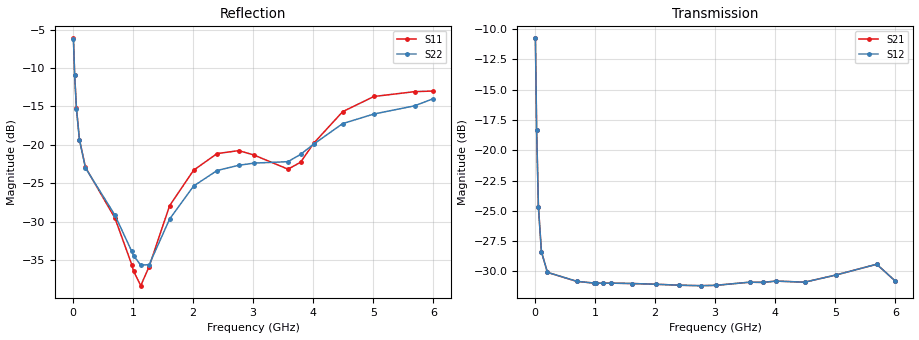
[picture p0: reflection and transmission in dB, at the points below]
! Integrated Device Technology
! Corporate Headquarters
! 6024 Silver Creek Valley Road
! San Jose, CA 95138  USA
! Phone:  1-408-284-8200
! Toll Free:  1-800-223-1366
! Webpage:  http://www.idt.com/
! Timing and RF Division
! 515 Groton Road, Suite 102
! Westford, MA 01886-6024
! Device:  F1951
! Description: 6-bit 0.5 dB Digital Step Attenuator
! Frequency:  100.0 -  4000.00 MHz
! Package:  4x4 mm Thin QFN Plastic Package: 24 pin
! Ports:  2 RF, 6 DC
!  Pin  1  = NC
!  Pin  2  = RF1  =  Port 1
!  Pin  3  = GND
!  Pin  4  = NC
!  Pin  5  = Serial Data Out (SDO)
!  Pin  6  = NC
!  Pin  7  = Reset Bar ( RSTb)
!  Pin  8  = Clock (CLK)
!  Pin  9  = Chip Select Bar (CSb)
!  Pin 10  = NC
!  Pin 11  = Serial Data In (SDI)
!  Pin 12  = NC
!  Pin 13  = NC
!  Pin 14  = VDD
!  Pin 15  = NC
!  Pin 16  = GND
!  Pin 17  = RF2  =  Port 2
!  Pin 18  = NC
!  Pin 19  = GND
!  Pin 20  = GND
!  Pin 21  = GND
!  Pin 22  = GND
!  Pin 23  = GND
!  Pin 24  = GND
! State:  60
! Atten State:  30.0 dB
! Voltage:  +3.30 Volts
! Current:  0.478 mA
! Data:  The device was measured on a F195X evaluation board which has
!  individual transmission lines to the RF pins.  Data was collected
!  de-embedded using a Automatic Fixture Removal [AFR] (Keysight Technologies).
!  The reference plane is the edge of the package pin.
! Misc:  Lot Code  1225BCA
!  Action Tracker AT0399
! Date Measured:  2018-09-13
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# GHz S dB R 50
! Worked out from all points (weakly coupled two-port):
!   600 points, 10 MHz to 6 GHz, reference 50 ohm
!   highest |S21| = -10.77 dB at 10 MHz (marker M1); lowest = -31.2 dB at 2.76 GHz (marker M2)
!   lowest |S11| = -38.3 dB at 1.13 GHz (marker M3), VSWR 1.02, Z = 48.8 + j0.211 ohm
!   |S11| at or under -10 dB: 25.95 MHz to end of sweep
!   |S22| runs from -36.1 to -6.2 dB; largest |S21 - S12| = 0.00018
!   S11 on the Smith chart (normalised r, x): 10 MHz: 1.78, -1.30; 30 MHz: 1.11, -0.62; 60 MHz: 0.98, -0.35; 980 MHz: 0.97, -0.01; 6 GHz: 0.81, +0.37
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0.01  -6.14 -34.1  -10.77 -41.3  -10.78 -41.3  -6.20 -34.0
0.03  -10.86 -63.8  -18.30 -67.6  -18.30 -67.7  -10.91 -63.7
0.06  -15.21 -83.4  -24.67 -61.9  -24.68 -61.9  -15.29 -83.4
0.11  -19.30 -101.2  -28.37 -44.2  -28.38 -44.1  -19.33 -101.2
0.21  -22.91 -119.5  -30.08 -27.1  -30.08 -27.1  -22.99 -119.5
0.7  -29.50 -136.3  -30.83 -14.6  -30.82 -14.6  -29.13 -138.5
0.98  -35.56 -152.7  -30.96 -15.0  -30.96 -15.0  -33.84 -150.4
1.01  -36.41 -157.7  -30.97 -15.0  -30.97 -15.0  -34.39 -153.2
1.13  -38.31 169.8  -30.98 -15.2  -30.98 -15.2  -35.63 -170.1
1.27  -35.82 132.3  -30.97 -15.9  -30.97 -15.8  -35.58 164.1
1.61  -27.91 115.4  -31.00 -17.9  -31.00 -17.9  -29.65 134.9
2.01  -23.29 123.1  -31.06 -21.0  -31.06 -21.0  -25.35 135.4
2.4  -21.13 133.3  -31.14 -23.7  -31.14 -23.7  -23.33 140.9
2.76  -20.74 142.1  -31.18 -26.2  -31.18 -26.1  -22.65 145.2
3.01  -21.30 145.8  -31.15 -27.7  -31.15 -27.7  -22.37 146.0
3.58  -23.15 124.7  -30.89 -31.5  -30.89 -31.5  -22.18 129.2
3.79  -22.26 109.0  -30.91 -33.0  -30.91 -33.0  -21.23 122.4
4.01  -19.77 100.6  -30.80 -34.6  -30.80 -34.6  -19.89 117.0
4.49  -15.68 98.9  -30.89 -37.2  -30.89 -37.2  -17.23 115.1
5.01  -13.70 107.6  -30.30 -38.0  -30.30 -38.0  -15.98 117.3
5.69  -13.07 112.5  -29.41 -49.4  -29.41 -49.4  -14.91 110.0
6  -12.99 106.2  -30.80 -48.7  -30.80 -48.7  -13.98 106.0
